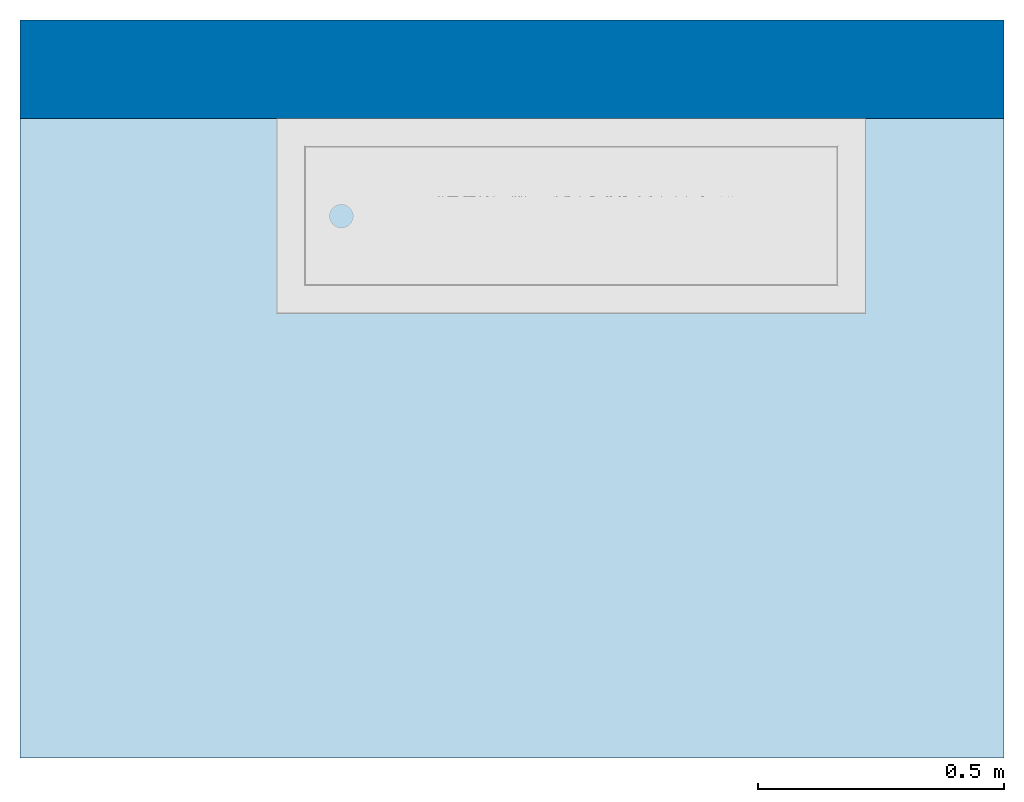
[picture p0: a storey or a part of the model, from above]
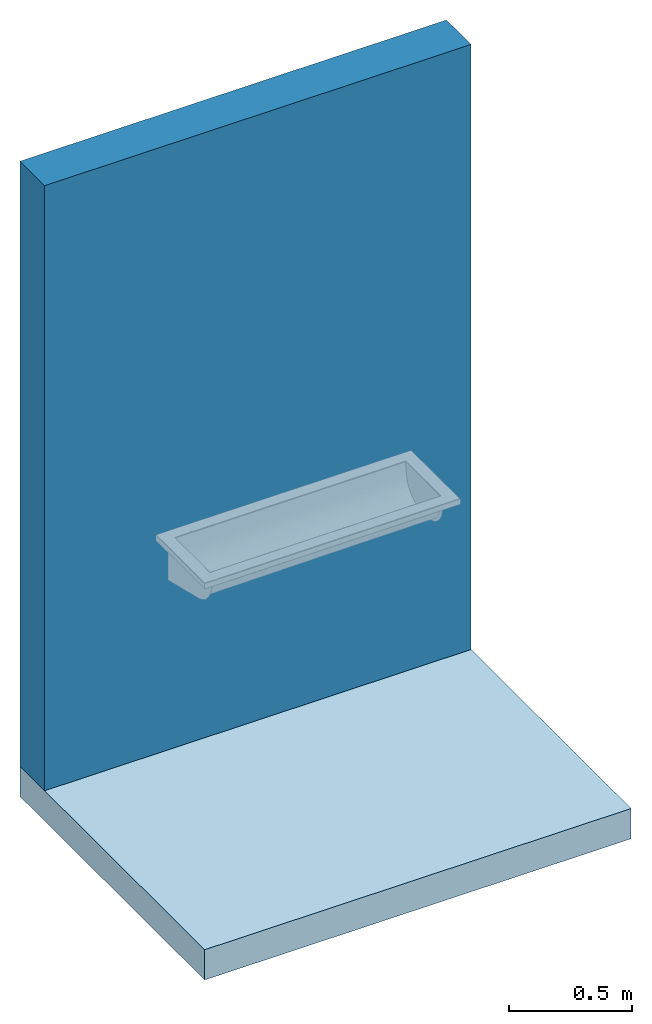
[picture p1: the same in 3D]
Properties of the parts of a building model (IFC2X3)

# File
Description: ViewDefinition [CoordinationView]
File name: 0001
Time: 2017-09-05T10:27:29
Written by: The EXPRESS Data Manager Version 5.02.0100.07 : 28 Aug 2013
Made in: 20160720_1515(x64) - Exporter 17.0.501.0 - Alternate UI 17.13.0.0
Comment: STEP Physical File produced by: The EXPRESS Data Manager Version 5.02.0100.07 : 28 Aug 2013 * Module: EDMstepFileFactory/EDMstandAlone * Creation date: Tue Sep 05 10:27:29 2017 * Host: Polantis_Siza * Database: C:\Users\POLANT~1\AppData\Local\Temp\{872423CE-90FC-4388-B475-C2B3BD8EE177}\ifc * Database version: 5507 * Database creation date: Tue Sep 05 10:27:27 2017 * Schema: IFC2X3 * Model: DataRepository.ifc * Model creation date: Tue Sep 05 10:27:27 2017 * Header model: DataRepository.ifc_HeaderModel * Header model creation date: Tue Sep 05 10:27:27 2017 * EDMuser: sdai-user * EDMgroup: sdai-group * License ID and type: 5605 : Permanent license. Expiry date: * EDMstepFileFactory options: 020000

# IfcProject, 0001
LongName: Project Name; Phase: Project Status

# IfcSite, Default
RefLatitude: 42, 21, 30, 344238; RefLongitude: -71, -3, -35, -194702; RefElevation: 0 mm
Other - Category: Project Information; Client Name: Owner; Project Address: Enter address here; Project Issue Date: Issue Date; Project Name: Project Name; Project Number: 0001; Project Status: Project Status

# IfcBuilding
Pset_BuildingCommon - NumberOfStoreys: 1
Other - Category: Project Information; Client Name: Owner; Project Address: Enter address here; Project Issue Date: Issue Date; Project Name: Project Name; Project Number: 0001; Project Status: Project Status

# IfcBuildingStorey, Level 1
LongName: Level 1; Elevation: 0 mm
Other - Category: Levels; Family Name: Level; Family: Level: 8mm Head; Family and Type: Level: 8mm Head; Type: Level: 8mm Head; Type Id: Level: 8mm Head
Identity Data - Type Name: 8mm Head; Structural: no; Building Story: yes; Name: Level 1
Constraints - Elevation: 0 mm; Elevation Base: Project Base Point
Dimensions - Computation Height: 0 mm
Graphics - Color: 0; Line Pattern: Centre; Line Weight: 1; Symbol: M_Level Head - Circle: M_Level Head - Circle; Symbol at End 1 Default: no; Symbol at End 2 Default: yes

# IfcFlowTerminal: Type 1, DLB070002-FR:Type 1:319662
In: Level 1
Material: 0211250015-23122015
Pset_ManufacturerTypeInformation - Manufacturer: DELABIE
Pset_DistributionFlowElementCommon - Reference: Type 1
Constraints - Elevation: 842.602 mm; Level: Level: Level 1
Dimensions - Area: 1.00117 m2; Volume: 0.00129463 m3; Radius: 23.8 mm
Identity Data - Mark: 4; Descriptif: Lavabo 2 places, à accrocher au mur. Inox 304 bactériostatique. Épaisseur Inox : 1 mm pour la cuve et 1,5 mm pour le contour et les équerres de montage. Pose facilitée : pas de couvre-joints à installer, lavabo léger. Écoulement à droite. Livré avec bonde 1"1/2. Sans trop-plein. Livré avec équerres de montage et fixations. Marquage CE. Conforme à la norme EN 14296. Poids : 8,4 kg. Possibilité d’ajouter un dosseret en Inox 304 bactériostatique, épaisseur Inox 1,2 mm (réf. 0011800002).; Description: DELABIE, fabricant français, est le leader européen de l'équipement sanitaire pour les établissements recevant du public. Robinetteries, solutions pour personnes à mobilité réduite, appareils sanitaires, destinés aux écoles, lieux de loisirs, bureaux, hôpitaux, aéroports, ...; Famille de produits: Lavabo; Finition: Inox 304 poli satiné; Hauteur: 180 mm; Largeur: 1200 mm; Lien CCTP: http://www.delabie.fr/produits/120250; Lien certification: http://www.delabie.fr/produits/120250; Lien fiche produit: http://www.delabie.fr/produits/120250; Lien notice d'installation: http://www.delabie.fr/produits/120250; Manufacturer: DELABIE; Model: CANAL; Profondeur: 400 mm; Référence: 120250; Type Comments: Lavabo collectif; Type Name: Type 1; URL: www.delabie.fr
Mechanical - System Classification: Sanitary
Other - Category: Plumbing Fixtures; Family: DLB070002-FR: Type 1; Family and Type: DLB070002-FR: Type 1; Host Id: Basic Wall: Generic - 200mm; Type: DLB070002-FR: Type 1; Type Id: DLB070002-FR: Type 1; Family Name: DLB070002-FR
Phasing - Phase Created: New Construction

# IfcSlab: Floor:Generic 150mm, Floor:Generic 150mm:309211
In: Level 1
PredefinedType: FLOOR; Material: Default Floor 150 mm
Pset_SlabCommon - Reference: Generic 150mm; IsExternal: no; LoadBearing: yes; PitchAngle: 0 deg
Constraints - Related to Mass: no; Room Bounding: yes; Height Offset From Level: 0 mm; Level: Level: Level 1
Dimensions - Area: 3 m2; Elevation at Bottom: -150 mm; Elevation at Top: 0 mm; Perimeter: 7000 mm; Thickness: 150 mm; Volume: 0.45 m3
Other - Category: Floors; Family: Floor: Generic 150mm; Family and Type: Floor: Generic 150mm; Type: Floor: Generic 150mm; Type Id: Floor: Generic 150mm; Family Name: Floor
Phasing - Phase Created: New Construction
Structural - Enable Analytical Model: no; Structural: no
Analytical Properties - Roughness: 3; Absorptance: 0.7
Construction - Default Thickness: 150 mm; Function: Interior
Graphics - Coarse Scale Fill Color: 0
Identity Data - Type Name: Generic 150mm

# IfcWallStandardCase: Basic Wall:Generic - 200mm, Basic Wall:Generic - 200mm:309152
In: Level 1
Type - PredefinedType: STANDARD; Material: Default Wall 200 mm
Type - Analytical Properties - Absorptance: 0.7; Roughness: 3
Type - Construction - Function: Exterior; Width: 200 mm; Wrapping at Inserts: Do not wrap
Type - Graphics - Coarse Scale Fill Color: 0
Type - Identity Data - Type Name: Generic - 200mm
Type - Other - Category: Walls; Family Name: Basic Wall
Constraints - Base Constraint: Level: Level 1; Base Extension Distance: 0 mm; Base is Attached: no; Base Offset: 0 mm; Location Line: Wall Centerline; Related to Mass: no; Room Bounding: yes; Top Extension Distance: 0 mm; Top is Attached: no; Top Offset: 0 mm; Unconnected Height: 3000 mm
Dimensions - Area: 6 m2; Length: 2000 mm; Volume: 1.2 m3
Other - Family: Basic Wall: Generic - 200mm; Family and Type: Basic Wall: Generic - 200mm; Type: Basic Wall: Generic - 200mm; Type Id: Basic Wall: Generic - 200mm
Phasing - Phase Created: New Construction
Structural - Enable Analytical Model: no; Structural: no; Structural Usage: Non-bearing
Pset_WallCommon - Reference: Generic - 200mm; LoadBearing: no; ExtendToStructure: no; IsExternal: yes
